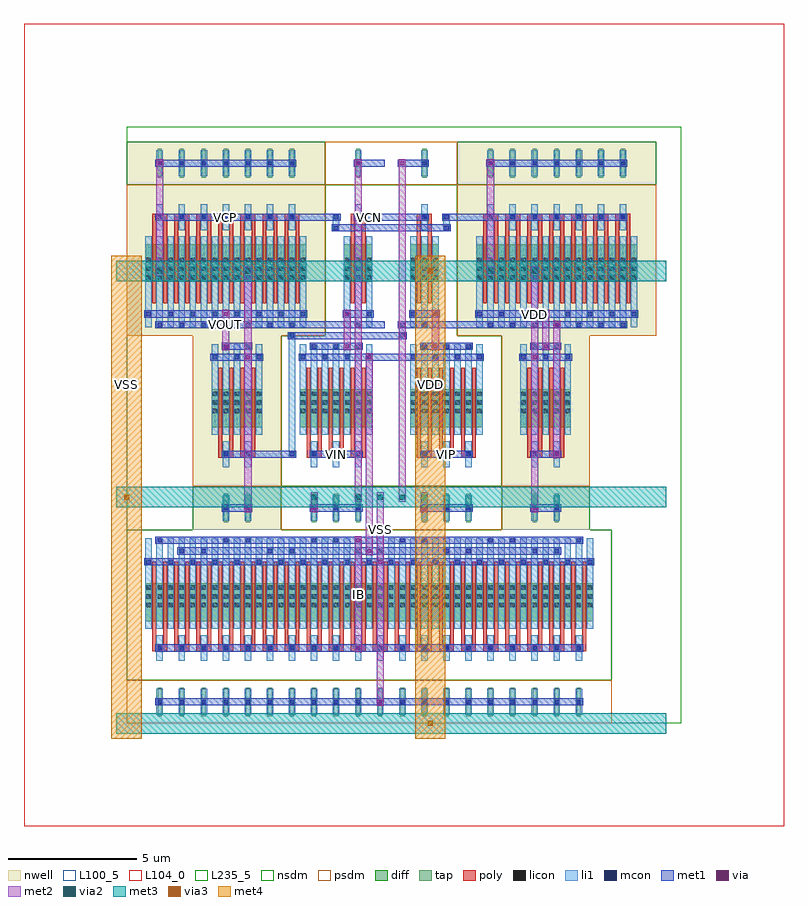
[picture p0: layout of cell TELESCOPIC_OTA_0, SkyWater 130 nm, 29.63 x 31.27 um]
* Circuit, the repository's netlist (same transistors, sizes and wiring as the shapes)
* NGSPICE file created from TELESCOPIC_OTA_0.ext - technology: sky130A

.subckt SCM_NMOS_15116351_X10_Y1_1774869217 a_402_420# a_200_252# a_147_420#
X0 a_147_420# a_200_252# a_402_420# a_147_420# sky130_fd_pr__nfet_01v8 ad=0.2058 pd=1.75 as=0.2058 ps=1.75 w=1.47 l=0.15 M=20
X1 a_147_420# a_200_252# a_200_252# a_147_420# sky130_fd_pr__nfet_01v8 ad=0.2058 pd=1.75 as=0.2058 ps=1.75 w=1.47 l=0.15 M=20
.ends

.subckt NMOS_4T_47642139_X3_Y1_1774869213 a_230_420# a_200_252# a_147_420# a_241_1232#
X0 a_147_420# a_200_252# a_230_420# a_241_1232# sky130_fd_pr__nfet_01v8 ad=0.2058 pd=1.75 as=0.2058 ps=1.75 w=1.47 l=0.15 M=6
.ends

.subckt PMOS_4T_843553_X7_Y1_1774869215 a_230_420# a_200_252# a_147_420# w_0_0#
X0 a_230_420# a_200_252# a_147_420# w_0_0# sky130_fd_pr__pfet_01v8 ad=0.2058 pd=1.75 as=0.2058 ps=1.75 w=1.47 l=0.15 M=14
.ends

.subckt NMOS_4T_91499272_X1_Y1_1774869214 a_230_420# a_200_252# a_147_420# a_241_1232#
X0 a_230_420# a_200_252# a_147_420# a_241_1232# sky130_fd_pr__nfet_01v8 ad=0.2058 pd=1.75 as=0.38955 ps=3.47 w=1.47 l=0.15 M=2
.ends

.subckt PMOS_S_44280068_X2_Y1_1774869216 a_230_420# a_200_252# w_0_0#
X0 a_230_420# a_200_252# w_0_0# w_0_0# sky130_fd_pr__pfet_01v8 ad=0.2058 pd=1.75 as=0.38955 ps=3.47 w=1.47 l=0.15 M=4
.ends

.subckt TELESCOPIC_OTA_0 IB VCN VOUT VIP VIN VCP VSS VDD
XSCM_NMOS_15116351_X10_Y1_1774869217_0 m1_1860_1316# IB VSS SCM_NMOS_15116351_X10_Y1_1774869217
XNMOS_4T_47642139_X3_Y1_1774869213_0 m1_1688_2912# VIN m1_1860_1316# VSS NMOS_4T_47642139_X3_Y1_1774869213
XNMOS_4T_47642139_X3_Y1_1774869213_1 m1_2376_2912# VIP m1_1860_1316# VSS NMOS_4T_47642139_X3_Y1_1774869213
XPMOS_4T_843553_X7_Y1_1774869215_0 VOUT VCP m1_742_2912# VDD PMOS_4T_843553_X7_Y1_1774869215
XPMOS_4T_843553_X7_Y1_1774869215_1 m1_3322_2072# VCP m1_3236_2912# VDD PMOS_4T_843553_X7_Y1_1774869215
XNMOS_4T_91499272_X1_Y1_1774869214_1 m1_3322_2072# VCN m1_2376_2912# VSS NMOS_4T_91499272_X1_Y1_1774869214
XNMOS_4T_91499272_X1_Y1_1774869214_0 VOUT VCN m1_1688_2912# VSS NMOS_4T_91499272_X1_Y1_1774869214
XPMOS_S_44280068_X2_Y1_1774869216_0 m1_742_2912# m1_3322_2072# VDD PMOS_S_44280068_X2_Y1_1774869216
XPMOS_S_44280068_X2_Y1_1774869216_1 m1_3236_2912# m1_3322_2072# VDD PMOS_S_44280068_X2_Y1_1774869216
.ends

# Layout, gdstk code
from math import pi, radians
import gdstk
lib = gdstk.Library(unit=1e-6, precision=1e-09)
def R(c, l, rs):  # rectangles x0, y0, x1, y1
    for r in rs: c.add(gdstk.rectangle(r[:2], r[2:], *l))
def A(c, l, x, y, w, h, nx, ny, dx, dy):  # array of equal rectangles
    R(c, l, [(x+i*dx, y+j*dy, x+i*dx+w, y+j*dy+h) for i in range(nx) for j in range(ny)])
def P(c, l, *ps):  # polygons
    for p in ps: c.add(gdstk.Polygon(p, *l))
nwell = (64, 20)
diff = (65, 20)
tap = (65, 44)
poly = (66, 20)
licon = (66, 44)
li1 = (67, 20)
mcon = (67, 44)
met1 = (68, 20)
via = (68, 44)
met2 = (69, 20)
via2 = (69, 44)
met3 = (70, 20)
via3 = (70, 44)
met4 = (71, 20)
nsdm = (93, 44)
psdm = (94, 20)
L100_5 = (100, 5)
L104_0 = (104, 0)
L235_5 = (235, 5)

scm_nmos_15116351_x10_y1 = lib.new_cell('SCM_NMOS_15116351_X10_Y1_1774869217')
R(scm_nmos_15116351_x10_y1, diff, [(0.735,2.1,18.185,3.57)])
A(scm_nmos_15116351_x10_y1, tap, 1.205, 6.16, 0.17, 1.12, 20, 1, 0.86, 0)
A(scm_nmos_15116351_x10_y1, poly, 1, 1.26, 0.15, 3.36, 40, 1, 0.43, 0)
A(scm_nmos_15116351_x10_y1, poly, 1, 4.485, 0.58, 0.27, 20, 1, 0.86, 0)
A(scm_nmos_15116351_x10_y1, licon, 0.775, 2.18, 0.17, 0.17, 3, 3, 0.43, 0.34)
A(scm_nmos_15116351_x10_y1, licon, 1.635, 2.18, 0.17, 0.17, 3, 3, 0.43, 0.34)
A(scm_nmos_15116351_x10_y1, licon, 2.495, 2.18, 0.17, 0.17, 3, 3, 0.43, 0.34)
A(scm_nmos_15116351_x10_y1, licon, 3.355, 2.18, 0.17, 0.17, 3, 3, 0.43, 0.34)
A(scm_nmos_15116351_x10_y1, licon, 4.215, 2.18, 0.17, 0.17, 3, 3, 0.43, 0.34)
A(scm_nmos_15116351_x10_y1, licon, 5.075, 2.18, 0.17, 0.17, 3, 3, 0.43, 0.34)
A(scm_nmos_15116351_x10_y1, licon, 5.935, 2.18, 0.17, 0.17, 3, 3, 0.43, 0.34)
A(scm_nmos_15116351_x10_y1, licon, 6.795, 2.18, 0.17, 0.17, 3, 3, 0.43, 0.34)
A(scm_nmos_15116351_x10_y1, licon, 7.655, 2.18, 0.17, 0.17, 3, 3, 0.43, 0.34)
A(scm_nmos_15116351_x10_y1, licon, 8.515, 2.18, 0.17, 0.17, 3, 3, 0.43, 0.34)
A(scm_nmos_15116351_x10_y1, licon, 9.375, 2.18, 0.17, 0.17, 3, 3, 0.43, 0.34)
A(scm_nmos_15116351_x10_y1, licon, 10.235, 2.18, 0.17, 0.17, 3, 3, 0.43, 0.34)
A(scm_nmos_15116351_x10_y1, licon, 11.095, 2.18, 0.17, 0.17, 3, 3, 0.43, 0.34)
A(scm_nmos_15116351_x10_y1, licon, 11.955, 2.18, 0.17, 0.17, 3, 3, 0.43, 0.34)
A(scm_nmos_15116351_x10_y1, licon, 12.815, 2.18, 0.17, 0.17, 3, 3, 0.43, 0.34)
A(scm_nmos_15116351_x10_y1, licon, 13.675, 2.18, 0.17, 0.17, 3, 3, 0.43, 0.34)
A(scm_nmos_15116351_x10_y1, licon, 14.535, 2.18, 0.17, 0.17, 3, 3, 0.43, 0.34)
A(scm_nmos_15116351_x10_y1, licon, 15.395, 2.18, 0.17, 0.17, 3, 3, 0.43, 0.34)
A(scm_nmos_15116351_x10_y1, licon, 16.255, 2.18, 0.17, 0.17, 3, 3, 0.43, 0.34)
A(scm_nmos_15116351_x10_y1, licon, 17.115, 2.18, 0.17, 0.17, 3, 3, 0.43, 0.34)
A(scm_nmos_15116351_x10_y1, licon, 1.205, 4.535, 0.17, 0.17, 20, 2, 0.86, 2.1)
A(scm_nmos_15116351_x10_y1, li1, 0.735, 0.335, 0.25, 3.53, 41, 1, 0.43, 0)
A(scm_nmos_15116351_x10_y1, li1, 1.165, 4.115, 0.25, 1.01, 20, 2, 0.86, 2.1)
A(scm_nmos_15116351_x10_y1, mcon, 0.775, 1.175, 0.17, 0.17, 21, 1, 0.86, 0)
A(scm_nmos_15116351_x10_y1, mcon, 1.205, 4.535, 0.17, 0.17, 20, 2, 0.86, 2.1)
R(scm_nmos_15116351_x10_y1, mcon, [(1.205,0.335,1.375,0.505), (3.785,0.335,3.955,0.505), (4.645,0.335,4.815,0.505), (7.225,0.335,7.395,0.505), (8.085,0.335,8.255,0.505), (10.665,0.335,10.835,0.505), (11.525,0.335,11.695,0.505), (14.105,0.335,14.275,0.505), (14.965,0.335,15.135,0.505), (17.545,0.335,17.715,0.505), (2.065,0.755,2.235,0.925), (2.925,0.755,3.095,0.925), (5.505,0.755,5.675,0.925), (6.365,0.755,6.535,0.925), (8.945,0.755,9.115,0.925), (9.805,0.755,9.975,0.925), (12.385,0.755,12.555,0.925), (13.245,0.755,13.415,0.925), (15.825,0.755,15.995,0.925), (16.685,0.755,16.855,0.925)])
R(scm_nmos_15116351_x10_y1, met1, [(1.12,0.28,17.8,0.56), (1.98,0.7,16.94,0.98), (0.69,1.12,18.23,1.4), (1.12,4.48,17.8,4.76), (1.12,6.58,17.8,6.86)])
R(scm_nmos_15116351_x10_y1, via, [(8.955,0.345,9.105,0.495), (9.815,1.185,9.965,1.335), (8.955,4.545,9.105,4.695), (9.815,6.645,9.965,6.795)])
R(scm_nmos_15116351_x10_y1, met2, [(8.89,0.26,9.17,4.78), (9.75,1.1,10.03,6.88)])
R(scm_nmos_15116351_x10_y1, nsdm, [(0,0,18.92,5.88)])
R(scm_nmos_15116351_x10_y1, psdm, [(0,5.88,18.92,7.56)])
R(scm_nmos_15116351_x10_y1, L100_5, [(0,0,18.92,7.56)])

pmos_s_44280068_x2_y1_17 = lib.new_cell('PMOS_S_44280068_X2_Y1_1774869216')
R(pmos_s_44280068_x2_y1_17, nwell, [(0,0,3.44,7.56)])
R(pmos_s_44280068_x2_y1_17, diff, [(0.735,2.1,2.705,3.57)])
R(pmos_s_44280068_x2_y1_17, tap, [(1.205,6.16,1.375,7.28), (2.065,6.16,2.235,7.28)])
A(pmos_s_44280068_x2_y1_17, poly, 1, 1.26, 0.15, 3.36, 4, 1, 0.43, 0)
R(pmos_s_44280068_x2_y1_17, poly, [(1,4.485,1.58,4.755), (1.86,4.485,2.44,4.755)])
A(pmos_s_44280068_x2_y1_17, licon, 0.775, 2.18, 0.17, 0.17, 3, 3, 0.43, 0.34)
A(pmos_s_44280068_x2_y1_17, licon, 1.635, 2.18, 0.17, 0.17, 3, 3, 0.43, 0.34)
R(pmos_s_44280068_x2_y1_17, licon, [(1.205,4.535,1.375,4.705), (2.065,4.535,2.235,4.705), (1.205,6.635,1.375,6.805), (2.065,6.635,2.235,6.805)])
A(pmos_s_44280068_x2_y1_17, li1, 0.735, 0.335, 0.25, 3.53, 5, 1, 0.43, 0)
R(pmos_s_44280068_x2_y1_17, li1, [(1.165,4.115,1.415,5.125), (2.025,4.115,2.275,5.125), (1.165,6.215,1.415,7.225), (2.025,6.215,2.275,7.225)])
A(pmos_s_44280068_x2_y1_17, mcon, 0.775, 0.755, 0.17, 0.17, 3, 1, 0.86, 0)
R(pmos_s_44280068_x2_y1_17, mcon, [(1.205,0.335,1.375,0.505), (2.065,0.335,2.235,0.505), (1.205,4.535,1.375,4.705), (2.065,4.535,2.235,4.705), (1.205,6.635,1.375,6.805), (2.065,6.635,2.235,6.805)])
R(pmos_s_44280068_x2_y1_17, met1, [(1.12,0.28,2.32,0.56), (0.69,0.7,2.75,0.98), (1.12,4.48,2.32,4.76), (1.12,6.58,2.32,6.86)])
R(pmos_s_44280068_x2_y1_17, via, [(2.075,0.765,2.225,0.915), (2.075,6.645,2.225,6.795)])
R(pmos_s_44280068_x2_y1_17, met2, [(2.01,0.68,2.29,6.88)])
R(pmos_s_44280068_x2_y1_17, nsdm, [(0,5.88,3.44,7.56)])
R(pmos_s_44280068_x2_y1_17, psdm, [(0,0,3.44,5.88)])
R(pmos_s_44280068_x2_y1_17, L100_5, [(0,0,3.44,7.56)])

nmos_4t_91499272_x1_y1_1 = lib.new_cell('NMOS_4T_91499272_X1_Y1_1774869214')
R(nmos_4t_91499272_x1_y1_1, diff, [(0.735,2.1,1.845,3.57)])
R(nmos_4t_91499272_x1_y1_1, tap, [(1.205,6.16,1.375,7.28)])
R(nmos_4t_91499272_x1_y1_1, poly, [(1,1.26,1.15,4.62), (1.43,1.26,1.58,4.62), (1,4.485,1.58,4.755)])
A(nmos_4t_91499272_x1_y1_1, licon, 0.775, 2.18, 0.17, 0.17, 3, 3, 0.43, 0.34)
R(nmos_4t_91499272_x1_y1_1, licon, [(1.205,4.535,1.375,4.705), (1.205,6.635,1.375,6.805)])
A(nmos_4t_91499272_x1_y1_1, li1, 0.735, 0.335, 0.25, 3.53, 3, 1, 0.43, 0)
R(nmos_4t_91499272_x1_y1_1, li1, [(1.165,4.115,1.415,5.125), (1.165,6.215,1.415,7.225)])
R(nmos_4t_91499272_x1_y1_1, mcon, [(1.205,0.335,1.375,0.505), (0.775,0.755,0.945,0.925), (1.635,0.755,1.805,0.925), (1.205,4.535,1.375,4.705), (1.205,6.635,1.375,6.805)])
R(nmos_4t_91499272_x1_y1_1, met1, [(0.26,0.28,1.46,0.56), (0.69,0.7,1.89,0.98), (0.26,4.48,1.46,4.76), (0.26,6.58,1.46,6.86)])
R(nmos_4t_91499272_x1_y1_1, nsdm, [(0,0,2.58,5.88)])
R(nmos_4t_91499272_x1_y1_1, psdm, [(0,5.88,2.58,7.56)])
R(nmos_4t_91499272_x1_y1_1, L100_5, [(0,0,2.58,7.56)])

nmos_4t_47642139_x3_y1_1 = lib.new_cell('NMOS_4T_47642139_X3_Y1_1774869213')
R(nmos_4t_47642139_x3_y1_1, diff, [(0.735,2.1,3.565,3.57)])
A(nmos_4t_47642139_x3_y1_1, tap, 1.205, 6.16, 0.17, 1.12, 3, 1, 0.86, 0)
A(nmos_4t_47642139_x3_y1_1, poly, 1, 1.26, 0.15, 3.36, 6, 1, 0.43, 0)
A(nmos_4t_47642139_x3_y1_1, poly, 1, 4.485, 0.58, 0.27, 3, 1, 0.86, 0)
A(nmos_4t_47642139_x3_y1_1, licon, 0.775, 2.18, 0.17, 0.17, 3, 3, 0.43, 0.34)
A(nmos_4t_47642139_x3_y1_1, licon, 1.635, 2.18, 0.17, 0.17, 3, 3, 0.43, 0.34)
A(nmos_4t_47642139_x3_y1_1, licon, 2.495, 2.18, 0.17, 0.17, 3, 3, 0.43, 0.34)
A(nmos_4t_47642139_x3_y1_1, licon, 1.205, 4.535, 0.17, 0.17, 3, 2, 0.86, 2.1)
A(nmos_4t_47642139_x3_y1_1, li1, 0.735, 0.335, 0.25, 3.53, 7, 1, 0.43, 0)
A(nmos_4t_47642139_x3_y1_1, li1, 1.165, 4.115, 0.25, 1.01, 3, 2, 0.86, 2.1)
A(nmos_4t_47642139_x3_y1_1, mcon, 1.205, 0.335, 0.17, 0.17, 3, 2, 0.86, 4.2)
A(nmos_4t_47642139_x3_y1_1, mcon, 0.775, 0.755, 0.17, 0.17, 4, 1, 0.86, 0)
A(nmos_4t_47642139_x3_y1_1, mcon, 1.205, 6.635, 0.17, 0.17, 3, 1, 0.86, 0)
R(nmos_4t_47642139_x3_y1_1, met1, [(1.12,0.28,3.18,0.56), (0.69,0.7,3.61,0.98), (1.12,4.48,3.18,4.76), (1.12,6.58,3.18,6.86)])
R(nmos_4t_47642139_x3_y1_1, nsdm, [(0,0,4.3,5.88)])
R(nmos_4t_47642139_x3_y1_1, psdm, [(0,5.88,4.3,7.56)])
R(nmos_4t_47642139_x3_y1_1, L100_5, [(0,0,4.3,7.56)])

pmos_4t_843553_x7_y1_177 = lib.new_cell('PMOS_4T_843553_X7_Y1_1774869215')
R(pmos_4t_843553_x7_y1_177, nwell, [(0,0,7.74,7.56)])
R(pmos_4t_843553_x7_y1_177, diff, [(0.735,2.1,7.005,3.57)])
A(pmos_4t_843553_x7_y1_177, tap, 1.205, 6.16, 0.17, 1.12, 7, 1, 0.86, 0)
A(pmos_4t_843553_x7_y1_177, poly, 1, 1.26, 0.15, 3.36, 14, 1, 0.43, 0)
A(pmos_4t_843553_x7_y1_177, poly, 1, 4.485, 0.58, 0.27, 7, 1, 0.86, 0)
A(pmos_4t_843553_x7_y1_177, licon, 0.775, 2.18, 0.17, 0.17, 3, 3, 0.43, 0.34)
A(pmos_4t_843553_x7_y1_177, licon, 1.635, 2.18, 0.17, 0.17, 3, 3, 0.43, 0.34)
A(pmos_4t_843553_x7_y1_177, licon, 2.495, 2.18, 0.17, 0.17, 3, 3, 0.43, 0.34)
A(pmos_4t_843553_x7_y1_177, licon, 3.355, 2.18, 0.17, 0.17, 3, 3, 0.43, 0.34)
A(pmos_4t_843553_x7_y1_177, licon, 4.215, 2.18, 0.17, 0.17, 3, 3, 0.43, 0.34)
A(pmos_4t_843553_x7_y1_177, licon, 5.075, 2.18, 0.17, 0.17, 3, 3, 0.43, 0.34)
A(pmos_4t_843553_x7_y1_177, licon, 5.935, 2.18, 0.17, 0.17, 3, 3, 0.43, 0.34)
A(pmos_4t_843553_x7_y1_177, licon, 1.205, 4.535, 0.17, 0.17, 7, 2, 0.86, 2.1)
A(pmos_4t_843553_x7_y1_177, li1, 0.735, 0.335, 0.25, 3.53, 15, 1, 0.43, 0)
A(pmos_4t_843553_x7_y1_177, li1, 1.165, 4.115, 0.25, 1.01, 7, 2, 0.86, 2.1)
A(pmos_4t_843553_x7_y1_177, mcon, 1.205, 0.335, 0.17, 0.17, 7, 2, 0.86, 4.2)
A(pmos_4t_843553_x7_y1_177, mcon, 0.775, 0.755, 0.17, 0.17, 8, 1, 0.86, 0)
A(pmos_4t_843553_x7_y1_177, mcon, 1.205, 6.635, 0.17, 0.17, 7, 1, 0.86, 0)
R(pmos_4t_843553_x7_y1_177, met1, [(1.12,0.28,6.62,0.56), (0.69,0.7,7.05,0.98), (1.12,4.48,6.62,4.76), (1.12,6.58,6.62,6.86)])
R(pmos_4t_843553_x7_y1_177, nsdm, [(0,5.88,7.74,7.56)])
R(pmos_4t_843553_x7_y1_177, psdm, [(0,0,7.74,5.88)])
R(pmos_4t_843553_x7_y1_177, L100_5, [(0,0,7.74,7.56)])

telescopic_ota_0 = lib.new_cell('TELESCOPIC_OTA_0')
R(telescopic_ota_0, li1, [(6.325,10.415,6.575,10.585), (6.325,10.415,6.575,10.585), (6.325,10.415,6.575,10.585), (6.325,10.415,6.575,10.585), (6.325,10.415,6.575,10.585), (6.325,10.415,6.575,10.585), (6.325,10.5,6.575,15.12), (6.325,15.035,6.575,15.205), (6.325,15.035,6.575,15.205), (6.325,15.035,6.575,15.205), (6.325,15.035,6.575,15.205), (6.325,15.035,6.575,15.205), (6.325,15.035,6.575,15.205), (10.625,15.035,10.875,15.205), (10.625,15.035,10.875,15.205), (10.625,15.035,10.875,15.205), (10.625,15.035,10.875,15.205), (10.625,15.035,10.875,15.205), (10.625,15.035,10.875,15.205), (10.625,15.12,10.875,15.54), (10.625,15.455,10.875,15.625), (10.625,15.455,10.875,15.625), (10.625,15.455,10.875,15.625), (10.625,15.455,10.875,15.625), (10.625,15.455,10.875,15.625), (10.625,15.455,10.875,15.625), (8.045,19.235,8.295,19.405), (8.045,19.235,8.295,19.405), (12.345,19.235,12.595,19.405), (12.345,19.235,12.595,19.405), (8.045,19.32,8.295,19.74), (12.345,19.32,12.595,19.74), (8.045,19.655,8.295,19.825), (8.045,19.655,8.295,19.825), (12.345,19.655,12.595,19.825), (12.345,19.655,12.595,19.825)])
R(telescopic_ota_0, mcon, [(6.365,10.415,6.535,10.585), (6.365,10.415,6.535,10.585), (6.365,10.415,6.535,10.585), (6.365,10.415,6.535,10.585), (6.365,10.415,6.535,10.585), (6.365,10.415,6.535,10.585), (6.365,15.035,6.535,15.205), (6.365,15.035,6.535,15.205), (6.365,15.035,6.535,15.205), (6.365,15.035,6.535,15.205), (6.365,15.035,6.535,15.205), (6.365,15.035,6.535,15.205), (10.665,15.035,10.835,15.205), (10.665,15.035,10.835,15.205), (10.665,15.035,10.835,15.205), (10.665,15.035,10.835,15.205), (10.665,15.035,10.835,15.205), (10.665,15.035,10.835,15.205), (10.665,15.455,10.835,15.625), (10.665,15.455,10.835,15.625), (10.665,15.455,10.835,15.625), (10.665,15.455,10.835,15.625), (10.665,15.455,10.835,15.625), (10.665,15.455,10.835,15.625), (8.085,19.235,8.255,19.405), (8.085,19.235,8.255,19.405), (12.385,19.235,12.555,19.405), (12.385,19.235,12.555,19.405), (8.085,19.655,8.255,19.825), (8.085,19.655,8.255,19.825), (12.385,19.655,12.555,19.825), (12.385,19.655,12.555,19.825)])
R(telescopic_ota_0, met1, [(9.3,6.58,9.62,6.86), (9.3,6.58,9.62,6.86), (9.3,6.58,9.62,6.86), (9.3,6.58,9.62,6.86), (7.15,8.26,7.47,8.54), (7.15,8.26,7.47,8.54), (11.45,8.26,11.77,8.54), (11.45,8.26,11.77,8.54), (11.45,8.26,11.77,8.54), (4.73,10.36,6.45,10.64), (6.28,10.36,6.62,10.64), (6.28,10.36,6.62,10.64), (6.28,10.36,6.62,10.64), (6.28,10.36,6.62,10.64), (6.28,10.36,6.62,10.64), (6.28,10.36,6.62,10.64), (16.61,10.36,16.93,10.64), (16.61,10.36,16.93,10.64), (9.3,14.14,9.62,14.42), (9.3,14.14,9.62,14.42), (9.3,14.14,9.62,14.42), (9.3,14.14,9.62,14.42), (9.46,14.14,11.18,14.42), (3.71,14.56,4.03,14.84), (3.71,14.56,4.03,14.84), (8.44,14.56,8.76,14.84), (8.44,14.56,8.76,14.84), (11.88,14.56,12.2,14.84), (11.88,14.56,12.2,14.84), (16.18,14.56,16.5,14.84), (16.18,14.56,16.5,14.84), (6.28,14.98,6.62,15.26), (6.28,14.98,6.62,15.26), (6.28,14.98,6.62,15.26), (6.28,14.98,6.62,15.26), (6.28,14.98,6.62,15.26), (6.28,14.98,6.62,15.26), (6.45,14.98,10.75,15.26), (10.58,14.98,10.92,15.26), (10.58,14.98,10.92,15.26), (10.58,14.98,10.92,15.26), (10.58,14.98,10.92,15.26), (10.58,14.98,10.92,15.26), (10.58,14.98,10.92,15.26), (6.45,15.4,9.03,15.68), (10.58,15.4,10.92,15.68), (10.58,15.4,10.92,15.68), (10.58,15.4,10.92,15.68), (10.58,15.4,10.92,15.68), (10.58,15.4,10.92,15.68), (10.58,15.4,10.92,15.68), (11.61,15.4,14.19,15.68), (16.61,15.4,16.93,15.68), (16.61,15.4,16.93,15.68), (3.71,15.82,4.03,16.1), (3.71,15.82,4.03,16.1), (8.44,15.82,8.76,16.1), (8.44,15.82,8.76,16.1), (11.88,15.82,12.2,16.1), (11.88,15.82,12.2,16.1), (16.18,15.82,16.5,16.1), (16.18,15.82,16.5,16.1), (8,19.18,8.34,19.46), (8,19.18,8.34,19.46), (8.17,19.18,12.47,19.46), (12.3,19.18,12.64,19.46), (12.3,19.18,12.64,19.46), (6.45,19.6,8.17,19.88), (8,19.6,8.34,19.88), (8,19.6,8.34,19.88), (9.89,19.6,10.75,19.88), (12.3,19.6,12.64,19.88), (12.3,19.6,12.64,19.88), (12.47,19.6,14.19,19.88), (1.13,21.7,1.45,21.98), (1.13,21.7,1.45,21.98), (8.87,21.7,9.19,21.98), (8.87,21.7,9.19,21.98), (8.87,21.7,9.19,21.98), (8.87,21.7,9.19,21.98), (10.59,21.7,10.91,21.98), (10.59,21.7,10.91,21.98), (10.59,21.7,10.91,21.98), (10.59,21.7,10.91,21.98), (10.59,21.7,10.91,21.98), (14.03,21.7,14.35,21.98), (14.03,21.7,14.35,21.98), (14.03,21.7,14.35,21.98)])
P(telescopic_ota_0, met1, [(0,0),(0,0),(0,0),(0,0)],
  [(0,0),(0,0),(0,0),(0,0)],
  [(0,0),(0,0),(0,0),(0,0)],
  [(0,0),(0,0),(0,0),(0,0)],
  [(0,0),(0,0),(0,0),(0,0)],
  [(0,0),(0,0),(0,0),(0,0)],
  [(0,0),(0,0),(0,0),(0,0)],
  [(0,0),(0,0),(0,0),(0,0)],
  [(0,0),(0,0),(0,0),(0,0)],
  [(0,0),(0,0),(0,0),(0,0)],
  [(0,0),(0,0),(0,0),(0,0)],
  [(0,0),(0,0),(0,0),(0,0)],
  [(0,0),(0,0),(0,0),(0,0)],
  [(0,0),(0,0),(0,0),(0,0)],
  [(0,0),(0,0),(0,0),(0,0)],
  [(0,0),(0,0),(0,0),(0,0)],
  [(0,0),(0,0),(0,0),(0,0)],
  [(0,0),(0,0),(0,0),(0,0)],
  [(0,0),(0,0),(0,0),(0,0)],
  [(0,0),(0,0),(0,0),(0,0)],
  [(0,0),(0,0),(0,0),(0,0)],
  [(0,0),(0,0),(0,0),(0,0)],
  [(0,0),(0,0),(0,0),(0,0)],
  [(0,0),(0,0),(0,0),(0,0)],
  [(0,0),(0,0),(0,0),(0,0)],
  [(0,0),(0,0),(0,0),(0,0)],
  [(0,0),(0,0),(0,0),(0,0)],
  [(0,0),(0,0),(0,0),(0,0)],
  [(0,0),(0,0),(0,0),(0,0)],
  [(0,0),(0,0),(0,0),(0,0)],
  [(0,0),(0,0),(0,0),(0,0)],
  [(0,0),(0,0),(0,0),(0,0)],
  [(0,0),(0,0),(0,0),(0,0)],
  [(0,0),(0,0),(0,0),(0,0)])
R(telescopic_ota_0, via, [(9.385,6.645,9.535,6.795), (9.385,6.645,9.535,6.795), (9.385,6.645,9.535,6.795), (9.385,6.645,9.535,6.795), (7.235,8.325,7.385,8.475), (7.235,8.325,7.385,8.475), (11.535,8.325,11.685,8.475), (11.535,8.325,11.685,8.475), (11.535,8.325,11.685,8.475), (16.695,10.425,16.845,10.575), (16.695,10.425,16.845,10.575), (9.385,14.205,9.535,14.355), (9.385,14.205,9.535,14.355), (9.385,14.205,9.535,14.355), (9.385,14.205,9.535,14.355), (3.795,14.625,3.945,14.775), (3.795,14.625,3.945,14.775), (8.525,14.625,8.675,14.775), (8.525,14.625,8.675,14.775), (11.965,14.625,12.115,14.775), (11.965,14.625,12.115,14.775), (16.265,14.625,16.415,14.775), (16.265,14.625,16.415,14.775), (16.695,15.465,16.845,15.615), (16.695,15.465,16.845,15.615), (3.795,15.885,3.945,16.035), (3.795,15.885,3.945,16.035), (8.525,15.885,8.675,16.035), (8.525,15.885,8.675,16.035), (11.965,15.885,12.115,16.035), (11.965,15.885,12.115,16.035), (16.265,15.885,16.415,16.035), (16.265,15.885,16.415,16.035), (1.215,21.765,1.365,21.915), (1.215,21.765,1.365,21.915), (8.955,21.765,9.105,21.915), (8.955,21.765,9.105,21.915), (8.955,21.765,9.105,21.915), (8.955,21.765,9.105,21.915), (10.675,21.765,10.825,21.915), (10.675,21.765,10.825,21.915), (10.675,21.765,10.825,21.915), (10.675,21.765,10.825,21.915), (10.675,21.765,10.825,21.915), (14.115,21.765,14.265,21.915), (14.115,21.765,14.265,21.915), (14.115,21.765,14.265,21.915)])
R(telescopic_ota_0, met2, [(9.75,6.3,10.03,8.82), (9.32,6.56,9.6,6.88), (9.32,6.56,9.6,6.88), (9.32,6.56,9.6,6.88), (9.32,6.56,9.6,6.88), (9.32,6.72,9.6,14.28), (7.17,8.24,7.45,8.56), (7.17,8.24,7.45,8.56), (11.47,8.24,11.75,8.56), (11.47,8.24,11.75,8.56), (11.47,8.24,11.75,8.56), (7.17,8.4,7.45,8.82), (11.47,8.4,11.75,8.82), (7.17,8.635,7.45,9.005), (7.17,8.635,7.45,9.005), (8.89,8.635,9.17,9.005), (8.89,8.635,9.17,9.005), (8.89,8.635,9.17,9.005), (8.89,8.635,9.17,9.005), (9.75,8.635,10.03,9.005), (9.75,8.635,10.03,9.005), (9.75,8.635,10.03,9.005), (9.75,8.635,10.03,9.005), (9.75,8.635,10.03,9.005), (9.75,8.635,10.03,9.005), (10.61,8.635,10.89,9.005), (10.61,8.635,10.89,9.005), (10.61,8.635,10.89,9.005), (10.61,8.635,10.89,9.005), (10.61,8.635,10.89,9.005), (11.47,8.635,11.75,9.005), (11.47,8.635,11.75,9.005), (11.47,8.635,11.75,9.005), (8.89,8.82,9.17,21.84), (10.61,8.82,10.89,21.84), (16.63,10.34,16.91,10.66), (16.63,10.34,16.91,10.66), (16.63,10.5,16.91,15.54), (9.32,14.12,9.6,14.44), (9.32,14.12,9.6,14.44), (9.32,14.12,9.6,14.44), (9.32,14.12,9.6,14.44), (4.59,14.28,4.87,17.64), (15.77,14.28,16.05,17.64), (3.73,14.54,4.01,14.86), (3.73,14.54,4.01,14.86), (8.46,14.54,8.74,14.86), (8.46,14.54,8.74,14.86), (11.9,14.54,12.18,14.86), (11.9,14.54,12.18,14.86), (16.2,14.54,16.48,14.86), (16.2,14.54,16.48,14.86), (3.73,14.7,4.01,15.96), (8.46,14.7,8.74,15.96), (11.9,14.7,12.18,15.96), (16.2,14.7,16.48,15.96), (16.63,15.38,16.91,15.7), (16.63,15.38,16.91,15.7), (3.73,15.8,4.01,16.12), (3.73,15.8,4.01,16.12), (8.46,15.8,8.74,16.12), (8.46,15.8,8.74,16.12), (11.9,15.8,12.18,16.12), (11.9,15.8,12.18,16.12), (16.2,15.8,16.48,16.12), (16.2,15.8,16.48,16.12), (1.15,17.455,1.43,17.825), (1.15,17.455,1.43,17.825), (4.59,17.455,4.87,17.825), (4.59,17.455,4.87,17.825), (4.59,17.455,4.87,17.825), (4.59,17.455,4.87,17.825), (14.05,17.455,14.33,17.825), (14.05,17.455,14.33,17.825), (14.05,17.455,14.33,17.825), (15.77,17.455,16.05,17.825), (15.77,17.455,16.05,17.825), (15.77,17.455,16.05,17.825), (15.77,17.455,16.05,17.825), (15.77,17.455,16.05,17.825), (1.15,17.64,1.43,21.84), (14.05,17.64,14.33,21.84), (1.15,21.68,1.43,22), (1.15,21.68,1.43,22), (8.89,21.68,9.17,22), (8.89,21.68,9.17,22), (8.89,21.68,9.17,22), (8.89,21.68,9.17,22), (10.61,21.68,10.89,22), (10.61,21.68,10.89,22), (10.61,21.68,10.89,22), (10.61,21.68,10.89,22), (10.61,21.68,10.89,22), (14.05,21.68,14.33,22), (14.05,21.68,14.33,22), (14.05,21.68,14.33,22)])
P(telescopic_ota_0, met2, [(0,0),(0,0),(0,0),(0,0)],
  [(0,0),(0,0),(0,0),(0,0)],
  [(0,0),(0,0),(0,0),(0,0)],
  [(0,0),(0,0),(0,0),(0,0)],
  [(0,0),(0,0),(0,0),(0,0)])
R(telescopic_ota_0, via2, [(7.21,8.72,7.41,8.92), (7.21,8.72,7.41,8.92), (8.93,8.72,9.13,8.92), (8.93,8.72,9.13,8.92), (8.93,8.72,9.13,8.92), (8.93,8.72,9.13,8.92), (9.79,8.72,9.99,8.92), (9.79,8.72,9.99,8.92), (9.79,8.72,9.99,8.92), (9.79,8.72,9.99,8.92), (9.79,8.72,9.99,8.92), (9.79,8.72,9.99,8.92), (10.65,8.72,10.85,8.92), (10.65,8.72,10.85,8.92), (10.65,8.72,10.85,8.92), (10.65,8.72,10.85,8.92), (10.65,8.72,10.85,8.92), (11.51,8.72,11.71,8.92), (11.51,8.72,11.71,8.92), (11.51,8.72,11.71,8.92), (1.19,17.54,1.39,17.74), (1.19,17.54,1.39,17.74), (4.63,17.54,4.83,17.74), (4.63,17.54,4.83,17.74), (4.63,17.54,4.83,17.74), (4.63,17.54,4.83,17.74), (14.09,17.54,14.29,17.74), (14.09,17.54,14.29,17.74), (14.09,17.54,14.29,17.74), (15.81,17.54,16.01,17.74), (15.81,17.54,16.01,17.74), (15.81,17.54,16.01,17.74), (15.81,17.54,16.01,17.74), (15.81,17.54,16.01,17.74)])
A(telescopic_ota_0, met3, -0.4, -0.4, 4.24, 0.8, 3, 3, 3.44, 8.82)
A(telescopic_ota_0, met3, 9.92, -0.4, 2.32, 0.8, 1, 3, 0, 8.82)
A(telescopic_ota_0, met3, 11.44, -0.4, 2.72, 0.8, 1, 3, 0, 8.82)
A(telescopic_ota_0, met3, 13.36, -0.4, 4.24, 0.8, 1, 3, 0, 8.82)
A(telescopic_ota_0, met3, 16.8, -0.4, 4.24, 0.8, 1, 3, 0, 8.82)
R(telescopic_ota_0, met3, [(11.675,-0.4,12.005,0.4), (-0.165,8.42,0.165,9.22), (7.145,8.42,7.475,9.22), (7.145,8.42,7.475,9.22), (8.865,8.42,9.195,9.22), (8.865,8.42,9.195,9.22), (8.865,8.42,9.195,9.22), (8.865,8.42,9.195,9.22), (9.725,8.42,10.055,9.22), (9.725,8.42,10.055,9.22), (9.725,8.42,10.055,9.22), (9.725,8.42,10.055,9.22), (9.725,8.42,10.055,9.22), (9.725,8.42,10.055,9.22), (10.585,8.42,10.915,9.22), (10.585,8.42,10.915,9.22), (10.585,8.42,10.915,9.22), (10.585,8.42,10.915,9.22), (10.585,8.42,10.915,9.22), (11.445,8.42,11.775,9.22), (11.445,8.42,11.775,9.22), (11.445,8.42,11.775,9.22), (1.125,17.24,1.455,18.04), (1.125,17.24,1.455,18.04), (4.565,17.24,4.895,18.04), (4.565,17.24,4.895,18.04), (4.565,17.24,4.895,18.04), (4.565,17.24,4.895,18.04), (11.675,17.24,12.005,18.04), (14.025,17.24,14.355,18.04), (14.025,17.24,14.355,18.04), (14.025,17.24,14.355,18.04), (15.745,17.24,16.075,18.04), (15.745,17.24,16.075,18.04), (15.745,17.24,16.075,18.04), (15.745,17.24,16.075,18.04), (15.745,17.24,16.075,18.04)])
R(telescopic_ota_0, via3, [(11.74,-0.1,11.94,0.1), (-0.1,8.72,0.1,8.92), (11.74,17.54,11.94,17.74)])
R(telescopic_ota_0, met4, [(-0.59,-0.59,0.59,9.41), (11.25,-0.59,12.43,9.41), (11.25,-0.165,12.43,0.165), (-0.59,8.23,0.59,18.23), (11.25,8.23,12.43,18.23), (-0.59,8.655,0.59,8.985), (11.25,17.475,12.43,17.805)])
R(telescopic_ota_0, L104_0, [(-4,-4,25.63,27.27)])
R(telescopic_ota_0, L235_5, [(0,0,21.63,23.27)])
telescopic_ota_0.add(gdstk.Reference(scm_nmos_15116351_x10_y1, (0,7.56), x_reflection=True))
telescopic_ota_0.add(gdstk.Reference(pmos_s_44280068_x2_y1_17, (18.06,15.12), rotation=pi))
telescopic_ota_0.add(gdstk.Reference(pmos_s_44280068_x2_y1_17, (2.58,15.12), x_reflection=True))
telescopic_ota_0.add(gdstk.Reference(nmos_4t_91499272_x1_y1_1, (10.32,15.12)))
telescopic_ota_0.add(gdstk.Reference(nmos_4t_91499272_x1_y1_1, (10.32,15.12), rotation=pi, x_reflection=True))
telescopic_ota_0.add(gdstk.Reference(nmos_4t_47642139_x3_y1_1, (14.62,15.12), rotation=pi))
telescopic_ota_0.add(gdstk.Reference(nmos_4t_47642139_x3_y1_1, (6.02,15.12), x_reflection=True))
telescopic_ota_0.add(gdstk.Reference(pmos_4t_843553_x7_y1_177, (12.9,15.12)))
telescopic_ota_0.add(gdstk.Reference(pmos_4t_843553_x7_y1_177, (7.74,15.12), rotation=pi, x_reflection=True))
telescopic_ota_0.add(gdstk.Label('IB', (9.03,5.04), layer=69, texttype=5))
telescopic_ota_0.add(gdstk.Label('VCN', (9.46,19.74), layer=68, texttype=5))
telescopic_ota_0.add(gdstk.Label('VOUT', (3.87,15.54), layer=68, texttype=5))
telescopic_ota_0.add(gdstk.Label('VIP', (12.47,10.5), layer=68, texttype=5))
telescopic_ota_0.add(gdstk.Label('VIN', (8.17,10.5), layer=68, texttype=5))
telescopic_ota_0.add(gdstk.Label('VCP', (3.87,19.74), layer=68, texttype=5))
telescopic_ota_0.add(gdstk.Label('VSS', (9.89,7.56), layer=69, texttype=5))
telescopic_ota_0.add(gdstk.Label('VSS', (0,13.23), layer=71, texttype=5))
telescopic_ota_0.add(gdstk.Label('VSS', (0,13.23), layer=71, texttype=5))
telescopic_ota_0.add(gdstk.Label('VSS', (0,13.23), layer=71, texttype=5))
telescopic_ota_0.add(gdstk.Label('VSS', (0,13.23), layer=71, texttype=5))
telescopic_ota_0.add(gdstk.Label('VSS', (0,13.23), layer=71, texttype=5))
telescopic_ota_0.add(gdstk.Label('VSS', (0,13.23), layer=71, texttype=5))
telescopic_ota_0.add(gdstk.Label('VSS', (0,13.23), layer=71, texttype=5))
telescopic_ota_0.add(gdstk.Label('VSS', (0,13.23), layer=71, texttype=5))
telescopic_ota_0.add(gdstk.Label('VSS', (0,13.23), layer=71, texttype=5))
telescopic_ota_0.add(gdstk.Label('VSS', (0,13.23), layer=71, texttype=5))
telescopic_ota_0.add(gdstk.Label('VSS', (0,13.23), layer=71, texttype=5))
telescopic_ota_0.add(gdstk.Label('VSS', (0,13.23), layer=71, texttype=5))
telescopic_ota_0.add(gdstk.Label('VSS', (0,13.23), layer=71, texttype=5))
telescopic_ota_0.add(gdstk.Label('VSS', (0,13.23), layer=71, texttype=5))
telescopic_ota_0.add(gdstk.Label('VDD', (15.91,15.96), layer=69, texttype=5))
telescopic_ota_0.add(gdstk.Label('VDD', (11.84,13.23), layer=71, texttype=5))
telescopic_ota_0.add(gdstk.Label('VDD', (11.84,13.23), layer=71, texttype=5))
telescopic_ota_0.add(gdstk.Label('VDD', (11.84,13.23), layer=71, texttype=5))
telescopic_ota_0.add(gdstk.Label('VDD', (11.84,13.23), layer=71, texttype=5))
telescopic_ota_0.add(gdstk.Label('VDD', (11.84,13.23), layer=71, texttype=5))
telescopic_ota_0.add(gdstk.Label('VDD', (11.84,13.23), layer=71, texttype=5))
telescopic_ota_0.add(gdstk.Label('VDD', (11.84,13.23), layer=71, texttype=5))
telescopic_ota_0.add(gdstk.Label('VDD', (11.84,13.23), layer=71, texttype=5))
telescopic_ota_0.add(gdstk.Label('VDD', (11.84,13.23), layer=71, texttype=5))
telescopic_ota_0.add(gdstk.Label('VDD', (11.84,13.23), layer=71, texttype=5))

lib.write_gds('TELESCOPIC_OTA_0.gds')
